One B-rep face of a CAD part: STEP entity #823.
In plain terms, the planar face has unit normal (0, 1, 0).
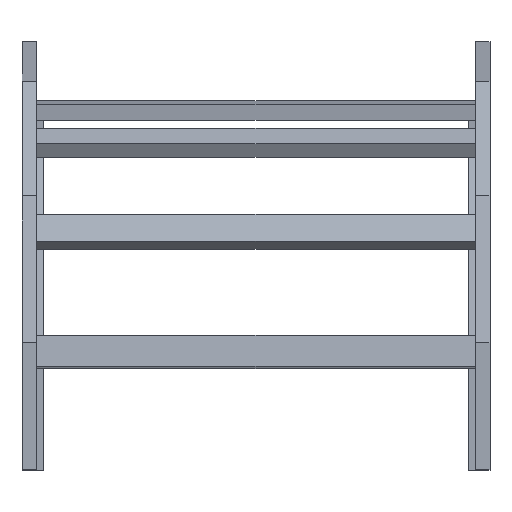
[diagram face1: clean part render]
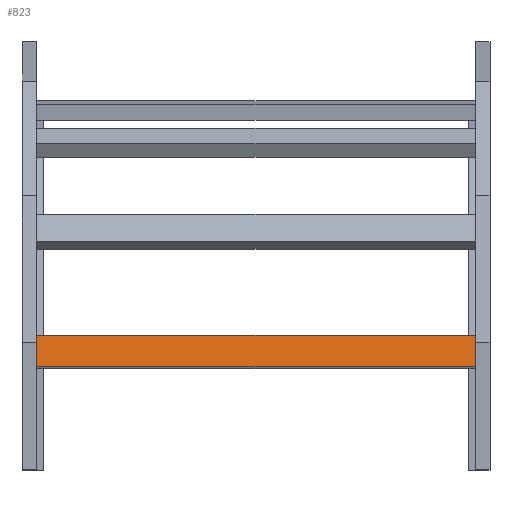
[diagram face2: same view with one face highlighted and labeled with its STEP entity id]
Its self-contained STEP definition (entity closure, numbers rounded to 3 decimals):
#75 = DIRECTION ( 'NONE',  ( -1., 0., 0. ) ) ;
#215 = DIRECTION ( 'NONE',  ( 0., -1., 0. ) ) ;
#279 = ORIENTED_EDGE ( 'NONE', *, *, #1452, .T. ) ;
#288 = ORIENTED_EDGE ( 'NONE', *, *, #621, .F. ) ;
#311 = LINE ( 'NONE', #1739, #773 ) ;
#342 = DIRECTION ( 'NONE',  ( 0., 0., 1. ) ) ;
#371 = PLANE ( 'NONE',  #994 ) ;
#381 = FACE_OUTER_BOUND ( 'NONE', #452, .T. ) ;
#398 = ORIENTED_EDGE ( 'NONE', *, *, #603, .T. ) ;
#412 = ORIENTED_EDGE ( 'NONE', *, *, #1271, .F. ) ;
#442 = DIRECTION ( 'NONE',  ( 0., 0., 1. ) ) ;
#452 = EDGE_LOOP ( 'NONE', ( #398, #412, #288, #279 ) ) ;
#481 = VERTEX_POINT ( 'NONE', #796 ) ;
#489 = VERTEX_POINT ( 'NONE', #1857 ) ;
#603 = EDGE_CURVE ( 'NONE', #481, #1258, #1035, .T. ) ;
#621 = EDGE_CURVE ( 'NONE', #836, #489, #311, .T. ) ;
#773 = VECTOR ( 'NONE', #442, 1000. ) ;
#791 = DIRECTION ( 'NONE',  ( -1., 0., 0. ) ) ;
#796 = CARTESIAN_POINT ( 'NONE',  ( -298., 20., -20.25 ) ) ;
#823 = ADVANCED_FACE ( 'NONE', ( #381 ), #371, .F. ) ;
#836 = VERTEX_POINT ( 'NONE', #957 ) ;
#936 = CARTESIAN_POINT ( 'NONE',  ( 298., 20., 20.25 ) ) ;
#957 = CARTESIAN_POINT ( 'NONE',  ( 298., 20., -20.25 ) ) ;
#994 = AXIS2_PLACEMENT_3D ( 'NONE', #1081, #215, #1385 ) ;
#1035 = LINE ( 'NONE', #1633, #1718 ) ;
#1081 = CARTESIAN_POINT ( 'NONE',  ( 298., 20., 20.25 ) ) ;
#1251 = LINE ( 'NONE', #1531, #1540 ) ;
#1258 = VERTEX_POINT ( 'NONE', #1505 ) ;
#1271 = EDGE_CURVE ( 'NONE', #489, #1258, #1533, .T. ) ;
#1385 = DIRECTION ( 'NONE',  ( 0., 0., -1. ) ) ;
#1452 = EDGE_CURVE ( 'NONE', #836, #481, #1251, .T. ) ;
#1505 = CARTESIAN_POINT ( 'NONE',  ( -298., 20., 20.25 ) ) ;
#1531 = CARTESIAN_POINT ( 'NONE',  ( 298., 20., -20.25 ) ) ;
#1533 = LINE ( 'NONE', #936, #1693 ) ;
#1540 = VECTOR ( 'NONE', #75, 1000. ) ;
#1633 = CARTESIAN_POINT ( 'NONE',  ( -298., 20., 20.25 ) ) ;
#1693 = VECTOR ( 'NONE', #791, 1000. ) ;
#1718 = VECTOR ( 'NONE', #342, 1000. ) ;
#1739 = CARTESIAN_POINT ( 'NONE',  ( 298., 20., 20.25 ) ) ;
#1857 = CARTESIAN_POINT ( 'NONE',  ( 298., 20., 20.25 ) ) ;
